VERSION 5.8 ;
BUSBITCHARS "[]" ;
DIVIDERCHAR "/" ;
UNITS
    DATABASE MICRONS 1000 ;
END UNITS

VIA delay_line_D4_O1_6P000_via1_2_1200_440_1_3_410_410
  VIARULE via1Array ;
  CUTSIZE 0.19 0.19 ;
  LAYERS Metal1 Via1 Metal2 ;
  CUTSPACING 0.22 0.22 ;
  ENCLOSURE 0.05 0.125 0.005 0.05 ;
  ROWCOL 1 3 ;
END delay_line_D4_O1_6P000_via1_2_1200_440_1_3_410_410

VIA delay_line_D4_O1_6P000_via2_3_1200_440_1_3_410_410
  VIARULE via2Array ;
  CUTSIZE 0.19 0.19 ;
  LAYERS Metal2 Via2 Metal3 ;
  CUTSPACING 0.22 0.22 ;
  ENCLOSURE 0.005 0.05 0.05 0.005 ;
  ROWCOL 1 3 ;
END delay_line_D4_O1_6P000_via2_3_1200_440_1_3_410_410

VIA delay_line_D4_O1_6P000_via3_4_1200_440_1_3_410_410
  VIARULE via3Array ;
  CUTSIZE 0.19 0.19 ;
  LAYERS Metal3 Via3 Metal4 ;
  CUTSPACING 0.22 0.22 ;
  ENCLOSURE 0.05 0.005 0.095 0.05 ;
  ROWCOL 1 3 ;
END delay_line_D4_O1_6P000_via3_4_1200_440_1_3_410_410

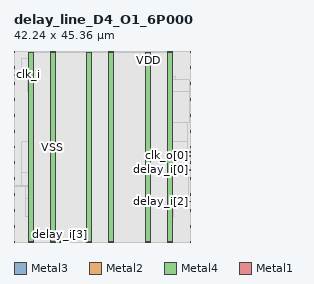
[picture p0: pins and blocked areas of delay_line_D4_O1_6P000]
MACRO delay_line_D4_O1_6P000
  FOREIGN delay_line_D4_O1_6P000 0 0 ;
  CLASS BLOCK ;
  SIZE 42.24 BY 45.36 ;
  PIN clk_i
    DIRECTION INPUT ;
    USE SIGNAL ;
    PORT
      LAYER Metal3 ;
        RECT  0 39.8 0.72 40 ;
    END
  END clk_i
  PIN clk_o[0]
    DIRECTION OUTPUT ;
    USE SIGNAL ;
    PORT
      LAYER Metal3 ;
        RECT  41.52 20.48 42.24 20.68 ;
    END
  END clk_o[0]
  PIN delay_i[0]
    DIRECTION INPUT ;
    USE SIGNAL ;
    PORT
      LAYER Metal3 ;
        RECT  41.52 17.12 42.24 17.32 ;
    END
  END delay_i[0]
  PIN delay_i[1]
    DIRECTION INPUT ;
    USE SIGNAL ;
    PORT
      LAYER Metal3 ;
        RECT  41.52 21.32 42.24 21.52 ;
    END
  END delay_i[1]
  PIN delay_i[2]
    DIRECTION INPUT ;
    USE SIGNAL ;
    PORT
      LAYER Metal3 ;
        RECT  41.52 9.56 42.24 9.76 ;
    END
  END delay_i[2]
  PIN delay_i[3]
    DIRECTION INPUT ;
    USE SIGNAL ;
    PORT
      LAYER Metal2 ;
        RECT  10.94 0 11.14 0.72 ;
    END
  END delay_i[3]
  PIN VSS
    DIRECTION INOUT ;
    USE GROUND ;
    PORT
      LAYER Metal4 ;
        RECT  36.6 45.16 37.8 45.36 ;
        RECT  36.6 0 37.8 0.2 ;
        RECT  36.6 -0.22 37.8 45.58 ;
        RECT  22.6 45.16 23.8 45.36 ;
        RECT  22.6 0 23.8 0.2 ;
        RECT  22.6 -0.22 23.8 45.58 ;
        RECT  8.6 45.16 9.8 45.36 ;
        RECT  8.6 0 9.8 0.2 ;
        RECT  8.6 -0.22 9.8 45.58 ;
      LAYER Metal1 ;
        RECT  42.08 45.14 42.24 45.58 ;
        RECT  0 45.14 0.16 45.58 ;
        RECT  42.08 37.58 42.24 38.02 ;
        RECT  0 37.58 0.16 38.02 ;
        RECT  42.08 30.02 42.24 30.46 ;
        RECT  0 30.02 0.16 30.46 ;
        RECT  42.08 22.46 42.24 22.9 ;
        RECT  0 22.46 0.16 22.9 ;
        RECT  42.08 14.9 42.24 15.34 ;
        RECT  0 14.9 0.16 15.34 ;
        RECT  42.08 7.34 42.24 7.78 ;
        RECT  0 7.34 0.16 7.78 ;
        RECT  42.08 -0.22 42.24 0.22 ;
        RECT  0 -0.22 0.16 0.22 ;
    END
  END VSS
  PIN VDD
    DIRECTION INOUT ;
    USE POWER ;
    PORT
      LAYER Metal4 ;
        RECT  31.4 45.16 32.6 45.36 ;
        RECT  31.4 0 32.6 0.2 ;
        RECT  31.4 0 32.6 45.36 ;
        RECT  17.4 45.16 18.6 45.36 ;
        RECT  17.4 0 18.6 0.2 ;
        RECT  17.4 0 18.6 45.36 ;
        RECT  3.4 45.16 4.6 45.36 ;
        RECT  3.4 0 4.6 0.2 ;
        RECT  3.4 0 4.6 45.36 ;
      LAYER Metal1 ;
        RECT  42.08 41.36 42.24 41.8 ;
        RECT  0 41.36 0.16 41.8 ;
        RECT  42.08 33.8 42.24 34.24 ;
        RECT  0 33.8 0.16 34.24 ;
        RECT  42.08 26.24 42.24 26.68 ;
        RECT  0 26.24 0.16 26.68 ;
        RECT  42.08 18.68 42.24 19.12 ;
        RECT  0 18.68 0.16 19.12 ;
        RECT  42.08 11.12 42.24 11.56 ;
        RECT  0 11.12 0.16 11.56 ;
        RECT  42.08 3.56 42.24 4 ;
        RECT  0 3.56 0.16 4 ;
    END
  END VDD
  OBS
    LAYER Metal1 ;
     RECT  0 -0.22 42.24 45.58 ;
    LAYER Metal2 ;
     RECT  8.69 -0.145 9.71 0.32 ;
     RECT  8.69 0.32 12.1 1.58 ;
     RECT  22.69 -0.145 23.71 1.58 ;
     RECT  36.69 -0.145 37.71 1.58 ;
     RECT  6.14 1.58 37.71 3.635 ;
     RECT  3.49 3.635 37.71 6.2 ;
     RECT  2.78 6.2 38.02 10.4 ;
     RECT  2.78 10.4 39.94 13.34 ;
     RECT  0.38 13.34 39.94 13.54 ;
     RECT  1.82 13.54 39.94 16.7 ;
     RECT  1.82 16.7 41.38 24.04 ;
     RECT  3.49 24.04 41.38 28.46 ;
     RECT  3.49 28.46 41.86 36.02 ;
     RECT  3.26 36.02 41.86 38.74 ;
     RECT  3.26 38.74 38.5 39.58 ;
     RECT  3.26 39.58 37.71 39.8 ;
     RECT  1.82 39.8 37.71 43.78 ;
     RECT  8.69 43.78 9.71 45.505 ;
     RECT  22.69 43.78 23.71 45.505 ;
     RECT  36.69 43.78 37.71 45.505 ;
    LAYER Metal3 ;
     RECT  0.48 39.8 3.26 40 ;
     RECT  3.26 39.8 3.445 40.42 ;
     RECT  3.445 3.68 8.645 41.68 ;
     RECT  8.645 -0.1 9.755 45.46 ;
     RECT  9.755 3.68 22.645 41.68 ;
     RECT  22.645 -0.1 23.755 45.46 ;
     RECT  23.755 2.84 36.645 41.68 ;
     RECT  36.645 -0.1 37.755 45.46 ;
     RECT  37.755 9.56 41.76 21.52 ;
    LAYER Metal4 ;
     RECT  8.6 -0.22 9.8 0 ;
     RECT  22.6 -0.22 23.8 0 ;
     RECT  36.6 -0.22 37.8 0 ;
     RECT  3.4 0 37.8 45.36 ;
     RECT  8.6 45.36 9.8 45.58 ;
     RECT  22.6 45.36 23.8 45.58 ;
     RECT  36.6 45.36 37.8 45.58 ;
  END
END delay_line_D4_O1_6P000
END LIBRARY
